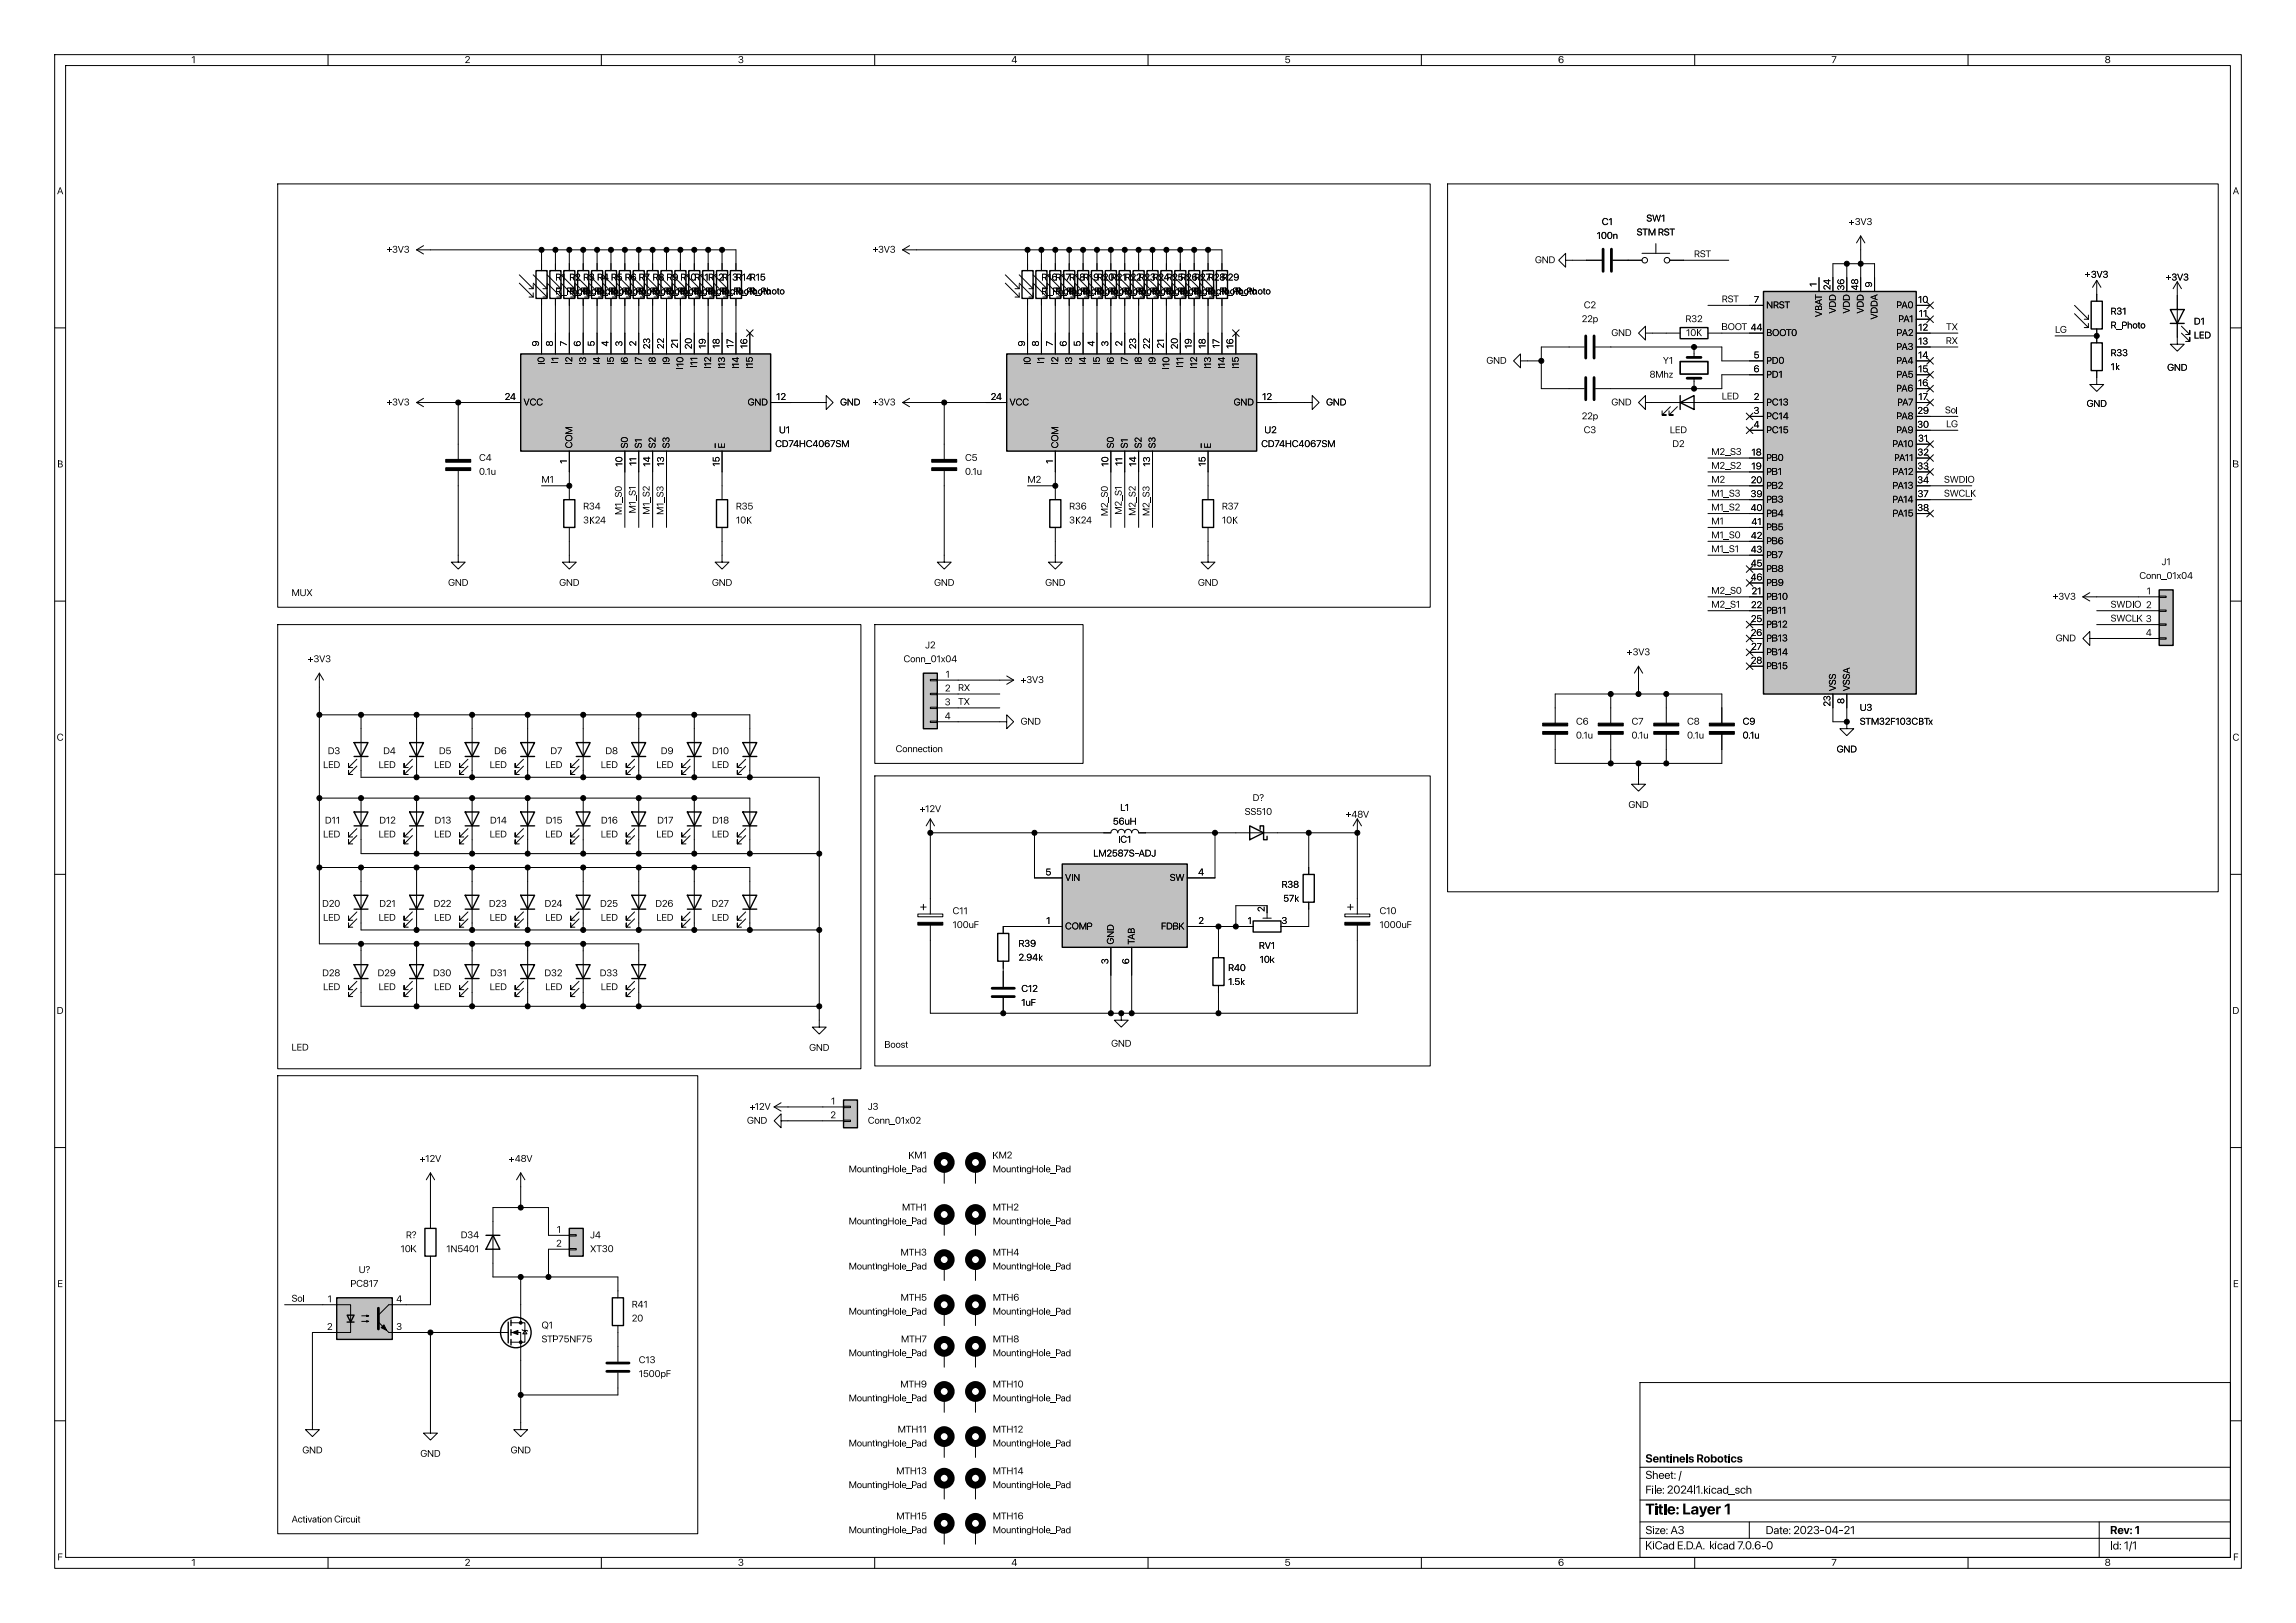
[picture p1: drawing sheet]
<svg xmlns="http://www.w3.org/2000/svg" width="420mm" height="297mm" viewBox="0 0 420 297" stroke-linecap="round" stroke-linejoin="round" font-family="sans-serif">
<defs><g id="words">
<text font-size="2.8" x="301" y="278">Title:Layer1</text>
<g font-size="2.1">
<text x="301" y="268.2">SentinelsRobotics</text>
<text x="301" y="273.9">File:2024l1.kicad_sch</text>
<text x="301" y="271.2">Sheet:/</text>
<text x="301" y="281.3">Size:A3</text>
<text x="323" y="281.3">Date:2023-04-21</text>
<text x="386" y="281.3">Rev:1</text>
<text x="301" y="284.1">KiCadE.D.A.kicad7.0.6-0</text>
<text x="386" y="284.1">Id:1/1</text>
</g>
<g font-size="1.8">
<text x="35" y="12.1">1</text>
<text x="85" y="12.1">2</text>
<text x="135" y="12.1">3</text>
<text x="185" y="12.1">4</text>
<text x="235" y="12.1">5</text>
<text x="285" y="12.1">6</text>
<text x="335" y="12.1">7</text>
<text x="385" y="12.1">8</text>
<text x="10.4" y="36.1">A</text>
<text x="293" y="41.7">C1</text>
<text x="301.2" y="41.1">SW1</text>
<text x="338.2" y="41.7">+3V3</text>
<text x="408.4" y="36.1">A</text>
<text x="70.7" y="46.8">+3V3</text>
<text x="159.6" y="46.8">+3V3</text>
<text x="292.1" y="44.2">100n</text>
<text x="299.4" y="43.6">STMRST</text>
<text x="309.9" y="47.3">RST</text>
<text x="101.6" y="51.9">R1R2R3R4R5R6R7R8R9R10R11R12R13R14R15</text>
<text x="190.5" y="51.9">R16R17R18R19R20R21R22R23R24R25R26R27R28R29</text>
<text x="280.8" y="48.7">GND</text>
<text x="332.5" y="52.5" transform="rotate(-90 332.5 52.5)">1</text>
<text x="335" y="53.1" transform="rotate(-90 335 53.1)">24</text>
<text x="337.6" y="53.1" transform="rotate(-90 337.6 53.1)">36</text>
<text x="340.1" y="53.1" transform="rotate(-90 340.1 53.1)">48</text>
<text x="342.6" y="52.6" transform="rotate(-90 342.6 52.6)">9</text>
<text x="381.4" y="51.3">+3V3</text>
<text x="396.1" y="51.9">+3V3</text>
<text x="101.6" y="54.4">R_Photo</text>
<text x="104.1" y="54.4">R_Photo</text>
<text x="106.7" y="54.4">R_Photo</text>
<text x="109.2" y="54.4">R_Photo</text>
<text x="116.8" y="54.4">R_Photo</text>
<text x="119.4" y="54.4">R_Photo</text>
<text x="127" y="54.4">R_Photo</text>
<text x="132.1" y="54.4">R_Photo</text>
<text x="134.6" y="54.4">R_Photo</text>
<text x="190.5" y="54.4">R_Photo</text>
<text x="193" y="54.4">R_Photo</text>
<text x="195.6" y="54.4">R_Photo</text>
<text x="200.7" y="54.4">R_Photo</text>
<text x="205.7" y="54.4">R_Photo</text>
<text x="210.8" y="54.4">R_Photo</text>
<text x="218.4" y="54.4">R_Photo</text>
<text x="223.5" y="54.4">R_Photo</text>
<text x="289.3" y="59.5">22p</text>
<text x="289.7" y="56.9">C2</text>
<text x="308.3" y="59.5">R32</text>
<text x="315" y="55.5">RST</text>
<text x="320.8" y="55.6">7</text>
<text x="323.1" y="56.9">NRST</text>
<text x="333.8" y="58" transform="rotate(-90 333.8 58)">VBAT</text>
<text x="336.3" y="57.4" transform="rotate(-90 336.3 57.4)">VDD</text>
<text x="338.9" y="57.4" transform="rotate(-90 338.9 57.4)">VDD</text>
<text x="341.4" y="57.4" transform="rotate(-90 341.4 57.4)">VDD</text>
<text x="344" y="58.5" transform="rotate(-90 344 58.5)">VDDA</text>
<text x="346.9" y="56.9">PA0</text>
<text x="347.2" y="59.5">PA1</text>
<text x="350.9" y="55.6">10</text>
<text x="351" y="58.2">11</text>
<text x="386.1" y="58.1">R31</text>
<text x="401.3" y="59.9">D1</text>
<text x="98.8" y="63.4" transform="rotate(-90 98.8 63.4)">9</text>
<text x="101.3" y="63.4" transform="rotate(-90 101.3 63.4)">8</text>
<text x="103.9" y="63.4" transform="rotate(-90 103.9 63.4)">7</text>
<text x="106.4" y="63.4" transform="rotate(-90 106.4 63.4)">6</text>
<text x="109" y="63.4" transform="rotate(-90 109 63.4)">5</text>
<text x="111.5" y="63.4" transform="rotate(-90 111.5 63.4)">4</text>
<text x="114" y="63.4" transform="rotate(-90 114 63.4)">3</text>
<text x="116.6" y="63.4" transform="rotate(-90 116.6 63.4)">2</text>
<text x="119.1" y="63.9" transform="rotate(-90 119.1 63.9)">23</text>
<text x="121.7" y="63.9" transform="rotate(-90 121.7 63.9)">22</text>
<text x="124.2" y="63.8" transform="rotate(-90 124.2 63.8)">21</text>
<text x="126.7" y="63.9" transform="rotate(-90 126.7 63.9)">20</text>
<text x="129.3" y="63.8" transform="rotate(-90 129.3 63.8)">19</text>
<text x="131.8" y="63.8" transform="rotate(-90 131.8 63.8)">18</text>
<text x="134.4" y="63.7" transform="rotate(-90 134.4 63.7)">17</text>
<text x="136.9" y="63.8" transform="rotate(-90 136.9 63.8)">16</text>
<text x="187.7" y="63.4" transform="rotate(-90 187.7 63.4)">9</text>
<text x="190.2" y="63.4" transform="rotate(-90 190.2 63.4)">8</text>
<text x="192.8" y="63.4" transform="rotate(-90 192.8 63.4)">7</text>
<text x="195.3" y="63.4" transform="rotate(-90 195.3 63.4)">6</text>
<text x="197.9" y="63.4" transform="rotate(-90 197.9 63.4)">5</text>
<text x="200.4" y="63.4" transform="rotate(-90 200.4 63.4)">4</text>
<text x="202.9" y="63.4" transform="rotate(-90 202.9 63.4)">3</text>
<text x="205.5" y="63.4" transform="rotate(-90 205.5 63.4)">2</text>
<text x="208" y="63.9" transform="rotate(-90 208 63.9)">23</text>
<text x="210.6" y="63.9" transform="rotate(-90 210.6 63.9)">22</text>
<text x="213.1" y="63.8" transform="rotate(-90 213.1 63.8)">21</text>
<text x="215.6" y="63.9" transform="rotate(-90 215.6 63.9)">20</text>
<text x="218.2" y="63.8" transform="rotate(-90 218.2 63.8)">19</text>
<text x="220.7" y="63.8" transform="rotate(-90 220.7 63.8)">18</text>
<text x="223.3" y="63.7" transform="rotate(-90 223.3 63.7)">17</text>
<text x="225.8" y="63.8" transform="rotate(-90 225.8 63.8)">16</text>
<text x="294.7" y="62">GND</text>
<text x="308.4" y="62">10K</text>
<text x="315" y="60.6">BOOT44</text>
<text x="320.2" y="60.7">44</text>
<text x="320.8" y="65.8">5</text>
<text x="323.1" y="62">BOOT0</text>
<text x="346.9" y="64.6">PA3</text>
<text x="346.9" y="62">PA2</text>
<text x="350.9" y="65.8">14</text>
<text x="350.9" y="63.2">13</text>
<text x="350.9" y="60.7">12</text>
<text x="355.9" y="63.2">RX</text>
<text x="356" y="60.6">TX</text>
<text x="375.9" y="61.1">LG</text>
<text x="386.1" y="60.6">R_Photo</text>
<text x="386.1" y="65.7">R33</text>
<text x="401.3" y="62.5">LED</text>
<text x="100.1" y="66.8" transform="rotate(-90 100.1 66.8)">I0</text>
<text x="102.7" y="66.5" transform="rotate(-90 102.7 66.5)">I1</text>
<text x="105.2" y="66.7" transform="rotate(-90 105.2 66.7)">I2</text>
<text x="107.7" y="66.7" transform="rotate(-90 107.7 66.7)">I3</text>
<text x="110.3" y="66.8" transform="rotate(-90 110.3 66.8)">I4</text>
<text x="112.8" y="66.7" transform="rotate(-90 112.8 66.7)">I5</text>
<text x="115.4" y="66.8" transform="rotate(-90 115.4 66.8)">I6</text>
<text x="117.9" y="66.6" transform="rotate(-90 117.9 66.6)">I7</text>
<text x="120.4" y="66.7" transform="rotate(-90 120.4 66.7)">I8</text>
<text x="123" y="66.8" transform="rotate(-90 123 66.8)">I9</text>
<text x="125.5" y="67.5" transform="rotate(-90 125.5 67.5)">I10</text>
<text x="128.1" y="67.3" transform="rotate(-90 128.1 67.3)">I11</text>
<text x="130.6" y="67.5" transform="rotate(-90 130.6 67.5)">I12</text>
<text x="133.1" y="67.5" transform="rotate(-90 133.1 67.5)">I13</text>
<text x="135.7" y="67.5" transform="rotate(-90 135.7 67.5)">I14</text>
<text x="138.2" y="67.5" transform="rotate(-90 138.2 67.5)">I15</text>
<text x="189" y="66.8" transform="rotate(-90 189 66.8)">I0</text>
<text x="191.6" y="66.5" transform="rotate(-90 191.6 66.5)">I1</text>
<text x="194.1" y="66.7" transform="rotate(-90 194.1 66.7)">I2</text>
<text x="196.6" y="66.7" transform="rotate(-90 196.6 66.7)">I3</text>
<text x="199.2" y="66.8" transform="rotate(-90 199.2 66.8)">I4</text>
<text x="201.7" y="66.7" transform="rotate(-90 201.7 66.7)">I5</text>
<text x="204.3" y="66.8" transform="rotate(-90 204.3 66.8)">I6</text>
<text x="206.8" y="66.6" transform="rotate(-90 206.8 66.6)">I7</text>
<text x="209.3" y="66.7" transform="rotate(-90 209.3 66.7)">I8</text>
<text x="211.9" y="66.8" transform="rotate(-90 211.9 66.8)">I9</text>
<text x="214.4" y="67.5" transform="rotate(-90 214.4 67.5)">I10</text>
<text x="217" y="67.3" transform="rotate(-90 217 67.3)">I11</text>
<text x="219.5" y="67.5" transform="rotate(-90 219.5 67.5)">I12</text>
<text x="222" y="67.5" transform="rotate(-90 222 67.5)">I13</text>
<text x="224.6" y="67.5" transform="rotate(-90 224.6 67.5)">I14</text>
<text x="227.1" y="67.5" transform="rotate(-90 227.1 67.5)">I15</text>
<text x="271.9" y="67.1">GND</text>
<text x="301.7" y="69.6">8Mhz</text>
<text x="304.2" y="67.1">Y1</text>
<text x="320.8" y="68.3">6</text>
<text x="323.1" y="67.1">PD0</text>
<text x="323.1" y="69.6">PD1</text>
<text x="346.9" y="67.1">PA4</text>
<text x="346.9" y="69.6">PA5</text>
<text x="350.8" y="70.9">16</text>
<text x="350.9" y="68.3">15</text>
<text x="386.1" y="68.2">1k</text>
<text x="396.4" y="68.4">GND</text>
<text x="70.7" y="74.7">+3V3</text>
<text x="92.3" y="73.4">24</text>
<text x="95.8" y="74.7">VCC</text>
<text x="136.8" y="74.7">GND</text>
<text x="142" y="73.4">12</text>
<text x="153.7" y="74.7">GND</text>
<text x="159.6" y="74.7">+3V3</text>
<text x="181.2" y="73.4">24</text>
<text x="184.7" y="74.7">VCC</text>
<text x="225.7" y="74.7">GND</text>
<text x="230.9" y="73.4">12</text>
<text x="242.6" y="74.7">GND</text>
<text x="289.3" y="77.3">22p</text>
<text x="294.7" y="74.7">GND</text>
<text x="315" y="73.3">LED</text>
<text x="320.8" y="75.9">3</text>
<text x="320.8" y="73.4">2</text>
<text x="323.1" y="74.7">PC13</text>
<text x="323.1" y="77.3">PC14</text>
<text x="346.9" y="72.2">PA6</text>
<text x="346.9" y="77.3">PA8</text>
<text x="347" y="74.7">PA7</text>
<text x="350.7" y="75.9">29</text>
<text x="350.9" y="73.4">17</text>
<text x="355.8" y="75.9">Sol</text>
<text x="381.7" y="75">GND</text>
<text x="105.2" y="82" transform="rotate(-90 105.2 82)">COM</text>
<text x="115.4" y="82" transform="rotate(-90 115.4 82)">S0</text>
<text x="117.9" y="82" transform="rotate(-90 117.9 82)">S1</text>
<text x="120.4" y="82" transform="rotate(-90 120.4 82)">S2</text>
<text x="123" y="82" transform="rotate(-90 123 82)">S3</text>
<text x="141.8" y="82.3">CD74HC4067SM</text>
<text x="142.5" y="79.8">U1</text>
<text x="194.1" y="82" transform="rotate(-90 194.1 82)">COM</text>
<text x="204.3" y="82" transform="rotate(-90 204.3 82)">S0</text>
<text x="206.8" y="82" transform="rotate(-90 206.8 82)">S1</text>
<text x="209.3" y="82" transform="rotate(-90 209.3 82)">S2</text>
<text x="211.9" y="82" transform="rotate(-90 211.9 82)">S3</text>
<text x="230.7" y="82.3">CD74HC4067SM</text>
<text x="231.3" y="79.8">U2</text>
<text x="289.7" y="79.8">C3</text>
<text x="305.5" y="79.8">LED</text>
<text x="305.9" y="82.3">D2</text>
<text x="313.1" y="83.5">M2_S3</text>
<text x="320.4" y="83.6">18</text>
<text x="320.8" y="78.5">4</text>
<text x="323.1" y="79.8">PC15</text>
<text x="346.2" y="82.3">PA10</text>
<text x="346.9" y="79.8">PA9</text>
<text x="350.7" y="78.5">30</text>
<text x="350.8" y="83.6">32</text>
<text x="350.9" y="81">31</text>
<text x="356" y="78.4">LG</text>
<text x="10.5" y="86.1">B</text>
<text x="87.6" y="84.9">C4</text>
<text x="87.6" y="87.4">0.1u</text>
<text x="99.1" y="88.6">M1</text>
<text x="103.9" y="84.8" transform="rotate(-90 103.9 84.8)">1</text>
<text x="114" y="85.4" transform="rotate(-90 114 85.4)">10</text>
<text x="116.6" y="85.2" transform="rotate(-90 116.6 85.2)">11</text>
<text x="119.1" y="85.4" transform="rotate(-90 119.1 85.4)">14</text>
<text x="121.7" y="85.4" transform="rotate(-90 121.7 85.4)">13</text>
<text x="131.8" y="85.4" transform="rotate(-90 131.8 85.4)">15</text>
<text x="176.5" y="84.9">C5</text>
<text x="176.5" y="87.4">0.1u</text>
<text x="188" y="88.6">M2</text>
<text x="192.8" y="84.8" transform="rotate(-90 192.8 84.8)">1</text>
<text x="202.9" y="85.4" transform="rotate(-90 202.9 85.4)">10</text>
<text x="205.5" y="85.2" transform="rotate(-90 205.5 85.2)">11</text>
<text x="208" y="85.4" transform="rotate(-90 208 85.4)">14</text>
<text x="210.6" y="85.4" transform="rotate(-90 210.6 85.4)">13</text>
<text x="220.7" y="85.4" transform="rotate(-90 220.7 85.4)">15</text>
<text x="313.1" y="86">M2_S2</text>
<text x="313.1" y="88.6">M2</text>
<text x="320.3" y="88.6">20</text>
<text x="320.4" y="86.1">19</text>
<text x="323.1" y="84.9">PB0</text>
<text x="323.1" y="87.4">PB1</text>
<text x="323.1" y="90">PB2</text>
<text x="346.2" y="90">PA13</text>
<text x="346.2" y="87.4">PA12</text>
<text x="346.4" y="84.9">PA11</text>
<text x="350.7" y="88.6">34</text>
<text x="350.7" y="86.1">33</text>
<text x="355.6" y="88.6">SWDIO</text>
<text x="408.4" y="86.1">B</text>
<text x="106.7" y="93.8">R34</text>
<text x="114" y="94.2" transform="rotate(-90 114 94.2)">M1_S0</text>
<text x="116.5" y="93.9" transform="rotate(-90 116.5 93.9)">M1_S1</text>
<text x="119" y="94.2" transform="rotate(-90 119 94.2)">M1_S2</text>
<text x="121.6" y="94.2" transform="rotate(-90 121.6 94.2)">M1_S3</text>
<text x="134.6" y="93.8">R35</text>
<text x="195.6" y="93.8">R36</text>
<text x="202.9" y="94.5" transform="rotate(-90 202.9 94.5)">M2_S0</text>
<text x="205.4" y="94.2" transform="rotate(-90 205.4 94.2)">M2_S1</text>
<text x="207.9" y="94.4" transform="rotate(-90 207.9 94.4)">M2_S2</text>
<text x="210.5" y="94.4" transform="rotate(-90 210.5 94.4)">M2_S3</text>
<text x="223.5" y="93.8">R37</text>
<text x="313.1" y="93.6">M1_S2</text>
<text x="313.1" y="91.1">M1_S3</text>
<text x="320.2" y="93.7">40</text>
<text x="320.2" y="91.2">39</text>
<text x="323.1" y="92.5">PB3</text>
<text x="323.1" y="95">PB4</text>
<text x="346.2" y="92.5">PA14</text>
<text x="346.2" y="95">PA15</text>
<text x="350.7" y="93.7">38</text>
<text x="350.8" y="91.2">37</text>
<text x="355.6" y="91.1">SWCLK</text>
<text x="106.7" y="96.3">3K24</text>
<text x="134.6" y="96.3">10K</text>
<text x="195.6" y="96.3">3K24</text>
<text x="223.5" y="96.3">10K</text>
<text x="313.1" y="98.7">M1_S0</text>
<text x="313.1" y="96.2">M1</text>
<text x="313.1" y="101.3">M1_S1</text>
<text x="320.2" y="101.3">43</text>
<text x="320.3" y="98.8">42</text>
<text x="320.4" y="96.3">41</text>
<text x="323.1" y="97.6">PB5</text>
<text x="323.1" y="100.1">PB6</text>
<text x="82" y="107.7">GND</text>
<text x="102.3" y="107.7">GND</text>
<text x="130.2" y="107.7">GND</text>
<text x="170.9" y="107.7">GND</text>
<text x="191.2" y="107.7">GND</text>
<text x="219.1" y="107.7">GND</text>
<text x="320.2" y="106.4">46</text>
<text x="320.3" y="103.9">45</text>
<text x="323.1" y="102.7">PB7</text>
<text x="323.1" y="105.2">PB8</text>
<text x="323.1" y="107.7">PB9</text>
<text x="391.3" y="106.5">Conn_01x04</text>
<text x="395.4" y="103.9">J1</text>
<text x="53.3" y="109.3">MUX</text>
<text x="313.1" y="111.4">M2_S1</text>
<text x="313.1" y="108.9">M2_S0</text>
<text x="320.3" y="111.5">22</text>
<text x="320.4" y="109">21</text>
<text x="323.1" y="110.3">PB10</text>
<text x="323.1" y="112.8">PB11</text>
<text x="375.5" y="110.3">+3V3</text>
<text x="386.1" y="111.4">SWDIO 2</text>
<text x="386.1" y="114">SWCLK3</text>
<text x="392.7" y="109">1</text>
<text x="169.2" y="119.2">J2</text>
<text x="320.3" y="116.6">26</text>
<text x="320.3" y="114">25</text>
<text x="320.3" y="119.1">27</text>
<text x="323.1" y="115.4">PB12</text>
<text x="323.1" y="117.9">PB13</text>
<text x="376" y="117.9">GND</text>
<text x="392.5" y="116.6">4</text>
<text x="56.3" y="121.7">+3V3</text>
<text x="165.3" y="121.7">Conn_01x04</text>
<text x="173" y="124.2">1</text>
<text x="186.7" y="125.5">+3V3</text>
<text x="297.6" y="120.4">+3V3</text>
<text x="320.3" y="121.7">28</text>
<text x="323.1" y="120.4">PB14</text>
<text x="323.1" y="123">PB15</text>
<text x="172.8" y="131.8">4</text>
<text x="172.8" y="129.3">3</text>
<text x="172.9" y="126.7">2</text>
<text x="175.3" y="129.2">TX</text>
<text x="175.3" y="126.7">RX</text>
<text x="335" y="129.3" transform="rotate(-90 335 129.3)">23</text>
<text x="336.3" y="126.5" transform="rotate(-90 336.3 126.5)">VSS</text>
<text x="337.6" y="128.8" transform="rotate(-90 337.6 128.8)">8</text>
<text x="338.9" y="126.5" transform="rotate(-90 338.9 126.5)">VSSA</text>
<text x="340.2" y="130.6">U3</text>
<text x="10.4" y="136.1">C</text>
<text x="163.8" y="137.8">Connection</text>
<text x="186.7" y="133.1">GND</text>
<text x="288.3" y="133.1">C6</text>
<text x="288.3" y="135.7">0.1u</text>
<text x="298.4" y="133.1">C7</text>
<text x="298.4" y="135.7">0.1u</text>
<text x="308.6" y="133.1">C8</text>
<text x="308.6" y="135.7">0.1u</text>
<text x="318.8" y="133.1">C9</text>
<text x="318.8" y="135.7">0.1u</text>
<text x="340.2" y="133.1">STM32F103CBTx</text>
<text x="408.4" y="136.1">C</text>
<text x="59.1" y="141.1">LED</text>
<text x="60" y="138.5">D3</text>
<text x="69.3" y="141.1">LED</text>
<text x="70.1" y="138.5">D4</text>
<text x="79.4" y="141.1">LED</text>
<text x="80.3" y="138.5">D5</text>
<text x="89.6" y="141.1">LED</text>
<text x="90.4" y="138.5">D6</text>
<text x="99.8" y="141.1">LED</text>
<text x="100.7" y="138.5">D7</text>
<text x="109.9" y="141.1">LED</text>
<text x="110.8" y="138.5">D8</text>
<text x="120.1" y="141.1">LED</text>
<text x="120.9" y="138.5">D9</text>
<text x="130.2" y="141.1">LED</text>
<text x="130.3" y="138.5">D10</text>
<text x="336" y="138.2">GND</text>
<text x="168.2" y="149.1">+12V</text>
<text x="204.9" y="148.9">L1</text>
<text x="227.7" y="149.6">SS510</text>
<text x="229.1" y="147.1">D?</text>
<text x="297.9" y="148.4">GND</text>
<text x="59.1" y="153.8">LED</text>
<text x="59.4" y="151.2">D11</text>
<text x="69.3" y="153.8">LED</text>
<text x="69.4" y="151.2">D12</text>
<text x="79.4" y="153.8">LED</text>
<text x="79.5" y="151.2">D13</text>
<text x="89.6" y="153.8">LED</text>
<text x="89.6" y="151.2">D14</text>
<text x="99.8" y="153.8">LED</text>
<text x="99.8" y="151.2">D15</text>
<text x="109.9" y="153.8">LED</text>
<text x="109.9" y="151.2">D16</text>
<text x="120.1" y="153.8">LED</text>
<text x="120.2" y="151.2">D17</text>
<text x="130.2" y="153.8">LED</text>
<text x="130.3" y="151.2">D18</text>
<text x="203.6" y="151.4">56uH</text>
<text x="204.5" y="154.7">IC1</text>
<text x="246.1" y="150.2">+48V</text>
<text x="191.3" y="160.4">5</text>
<text x="194.8" y="161.7">VIN</text>
<text x="200" y="157.3">LM2587S-ADJ</text>
<text x="214" y="161.7">SW</text>
<text x="219.2" y="160.4">4</text>
<text x="58.9" y="166.5">D20</text>
<text x="69.4" y="166.5">D21</text>
<text x="79.3" y="166.5">D22</text>
<text x="89.4" y="166.5">D23</text>
<text x="99.6" y="166.5">D24</text>
<text x="109.8" y="166.5">D25</text>
<text x="119.9" y="166.5">D26</text>
<text x="130.2" y="166.5">D27</text>
<text x="174.2" y="167.8">C11</text>
<text x="231.5" y="166.9" transform="rotate(-90 231.5 166.9)">2</text>
<text x="234.4" y="163">R38</text>
<text x="234.7" y="165.5">57k</text>
<text x="252.3" y="167.8">C10</text>
<text x="59.1" y="169">LED</text>
<text x="69.3" y="169">LED</text>
<text x="79.4" y="169">LED</text>
<text x="89.6" y="169">LED</text>
<text x="99.8" y="169">LED</text>
<text x="109.9" y="169">LED</text>
<text x="120.1" y="169">LED</text>
<text x="130.2" y="169">LED</text>
<text x="174.2" y="170.3">100uF</text>
<text x="186.3" y="173.8">R39</text>
<text x="191.4" y="169.3">1</text>
<text x="194.8" y="170.6">COMP</text>
<text x="204.3" y="172.8" transform="rotate(-90 204.3 172.8)">GND</text>
<text x="208.1" y="172.8" transform="rotate(-90 208.1 172.8)">TAB</text>
<text x="212.4" y="170.6">FDBK</text>
<text x="219.2" y="169.3">2</text>
<text x="228.2" y="169.3">1</text>
<text x="234.4" y="169.3">3</text>
<text x="252.3" y="170.3">1000uF</text>
<text x="59" y="179.2">D28</text>
<text x="69.1" y="179.2">D29</text>
<text x="79.2" y="179.2">D30</text>
<text x="89.7" y="179.2">D31</text>
<text x="99.6" y="179.2">D32</text>
<text x="109.7" y="179.2">D33</text>
<text x="186.3" y="176.3">2.94k</text>
<text x="202.9" y="176.4" transform="rotate(-90 202.9 176.4)">3</text>
<text x="206.8" y="176.4" transform="rotate(-90 206.8 176.4)">6</text>
<text x="224.7" y="178.2">R40</text>
<text x="230.3" y="174.2">RV1</text>
<text x="230.4" y="176.7">10k</text>
<text x="59.1" y="181.7">LED</text>
<text x="69.3" y="181.7">LED</text>
<text x="79.4" y="181.7">LED</text>
<text x="89.6" y="181.7">LED</text>
<text x="99.8" y="181.7">LED</text>
<text x="109.9" y="181.7">LED</text>
<text x="186.8" y="182">C12</text>
<text x="186.8" y="184.6">1uF</text>
<text x="224.7" y="180.8">1.5k</text>
<text x="10.4" y="186.1">D</text>
<text x="161.8" y="191.9">Boost</text>
<text x="408.4" y="186.1">D</text>
<text x="53.3" y="192.5">LED</text>
<text x="148" y="192.8">GND</text>
<text x="203.3" y="192.1">GND</text>
<text x="137" y="203.6">+12V</text>
<text x="152" y="202.3">1</text>
<text x="158.7" y="203.6">J3</text>
<text x="136.6" y="206.2">GND</text>
<text x="151.9" y="204.9">2</text>
<text x="158.7" y="206.2">Conn_01x02</text>
<text x="76.8" y="213.1">+12V</text>
<text x="93.1" y="213.1">+48V</text>
<text x="155.3" y="215">MountingHole_Pad</text>
<text x="166.2" y="212.5">KM1</text>
<text x="181.6" y="212.5">KM2</text>
<text x="181.6" y="215">MountingHole_Pad</text>
<text x="74.3" y="227.1">R?</text>
<text x="84.3" y="227.1">D34</text>
<text x="101.8" y="225.8">1</text>
<text x="107.9" y="227.1">J4</text>
<text x="155.3" y="224.6">MountingHole_Pad</text>
<text x="165" y="222">MTH1</text>
<text x="181.6" y="222">MTH2</text>
<text x="181.6" y="224.6">MountingHole_Pad</text>
<text x="65.6" y="233.5">U?</text>
<text x="73.3" y="229.7">10K</text>
<text x="81.6" y="229.7">1N5401</text>
<text x="101.7" y="228.3">2</text>
<text x="107.9" y="229.7">XT30</text>
<text x="155.3" y="232.8">MountingHole_Pad</text>
<text x="164.7" y="230.3">MTH3</text>
<text x="181.6" y="230.3">MTH4</text>
<text x="181.6" y="232.8">MountingHole_Pad</text>
<text x="10.5" y="236.1">E</text>
<text x="53.3" y="238.4">Sol</text>
<text x="59.9" y="238.5">1</text>
<text x="64.1" y="236">PC817</text>
<text x="72.5" y="238.5">4</text>
<text x="115.6" y="239.8">R41</text>
<text x="164.8" y="238.5">MTH5</text>
<text x="181.6" y="238.5">MTH6</text>
<text x="408.5" y="236.1">E</text>
<text x="59.8" y="243.6">2</text>
<text x="72.5" y="243.6">3</text>
<text x="99.1" y="243.6">Q1</text>
<text x="115.6" y="242.4">20</text>
<text x="155.3" y="241.1">MountingHole_Pad</text>
<text x="181.6" y="241.1">MountingHole_Pad</text>
<text x="99.1" y="246.2">STP75NF75</text>
<text x="116.8" y="250">C13</text>
<text x="155.3" y="248.7">MountingHole_Pad</text>
<text x="164.8" y="246.2">MTH7</text>
<text x="181.6" y="246.2">MTH8</text>
<text x="181.6" y="248.7">MountingHole_Pad</text>
<text x="116.8" y="252.5">1500pF</text>
<text x="155.3" y="257">MountingHole_Pad</text>
<text x="164.7" y="254.4">MTH9</text>
<text x="181.6" y="254.4">MTH10</text>
<text x="181.6" y="257">MountingHole_Pad</text>
<text x="164.2" y="262.7">MTH11</text>
<text x="181.6" y="262.7">MTH12</text>
<text x="55.3" y="266.5">GND</text>
<text x="76.9" y="267.1">GND</text>
<text x="93.4" y="266.5">GND</text>
<text x="155.3" y="265.2">MountingHole_Pad</text>
<text x="181.6" y="265.2">MountingHole_Pad</text>
<text x="155.3" y="272.8">MountingHole_Pad</text>
<text x="164" y="270.3">MTH13</text>
<text x="181.6" y="270.3">MTH14</text>
<text x="181.6" y="272.8">MountingHole_Pad</text>
<text x="53.3" y="278.8">ActivationCircuit</text>
<text x="155.3" y="281.1">MountingHole_Pad</text>
<text x="164" y="278.5">MTH15</text>
<text x="181.6" y="278.5">MTH16</text>
<text x="181.6" y="281.1">MountingHole_Pad</text>
<text x="10.5" y="286.1">F</text>
<text x="35" y="287.1">1</text>
<text x="85" y="287.1">2</text>
<text x="135" y="287.1">3</text>
<text x="185" y="287.1">4</text>
<text x="235" y="287.1">5</text>
<text x="285" y="287.1">6</text>
<text x="335" y="287.1">7</text>
<text x="385" y="287.1">8</text>
<text x="408.5" y="286.1">F</text>
</g>
</g></defs>
<g fill="none" stroke="#000" stroke-width=".18">
<path d="M10 10h400v277h-400zM12 12h396v273h-396zM60 10v2M110 10v2M160 10v2M210 10v2M260 10v2M310 10v2M360 10v2M50.8 33.7h210.8v77.4h-210.8zM264.8 33.7h141v129.5h-141zM10 60h2"/>
<path d="M76.2 45.7h58.4v3.8M76.2 45.7l1.3 .8M77.5 45l-1.3 .7M95 51.8l2.5 2.6M95 50.3l2.5 2.5M96.8 54.4h.7M96.8 52.8h.7M97.5 51.8l2.6 2.6M97.5 50.3l2.6 2.5M97.5 52.1v.7M97.5 53.6v.8M99.1 45.7v3.8"/>
<path d="M99.1 54.6v10.2M99.3 54.4h.8M99.3 52.8h.8M100.1 52.1v.7M100.1 53.6v.8M100.1 51.8l2.5 2.6M100.1 50.3l2.5 2.5v-.7M101.6 45.7v3.8M101.6 54.6v10.2M102.6 51.8l2.6 2.6M102.6 50.3l2.6 2.5v-.7M104.1 45.7v3.8"/>
<path d="M104.1 54.6v10.2M105.2 51.8l2.5 2.6M105.2 50.3l2.5 2.5v-.7M106.7 45.7v3.8M106.7 54.6v10.2M107.7 51.8l2.5 2.6M107.7 50.3l2.5 2.5v-.7M109.2 45.7v3.8M109.2 54.6v10.2M110.2 51.8l2.6 2.6M110.2 50.3l2.6 2.5v-.7M111.8 45.7v3.8"/>
<path d="M111.8 54.6v10.2M112.8 51.8l2.5 2.6M112.8 50.3l2.5 2.5v-.7M114.3 45.7v3.8M114.3 54.6v10.2M115.3 51.8l2.6 2.6M115.3 50.3l2.6 2.5v-.7M116.8 45.7v3.8M116.8 54.6v10.2M117.9 51.8l2.5 2.6M117.9 50.3l2.5 2.5v-.7M119.4 45.7v3.8"/>
<path d="M119.4 54.6v10.2M120.4 51.8l2.5 2.6M120.4 50.3l2.5 2.5v-.7M121.9 45.7v3.8M121.9 54.6v10.2M122.9 51.8l2.6 2.6M122.9 50.3l2.6 2.5v-.7M124.5 45.7v3.8M124.5 54.6v10.2M125.5 51.8l2.5 2.6M125.5 50.3l2.5 2.5v-.7M127 45.7v3.8"/>
<path d="M127 54.6v10.2M128 51.8l2.6 2.6M128 50.3l2.6 2.5v-.7M129.5 45.7v3.8M129.5 54.6v10.2M130.6 51.8l2.5 2.6M130.6 50.3l2.5 2.5v-.7M132.1 45.7v3.8M132.1 54.6v10.2M134.6 54.6v10.2M165.1 45.7h58.4v3.8M165.1 45.7l1.3 .8"/>
<path d="M166.4 45l-1.3 .7M183.9 51.8l2.5 2.6M183.9 50.3l2.5 2.5M185.7 54.4h.7M185.7 52.8h.7M186.4 52.1v.7M186.4 53.6v.8M186.4 51.8l2.6 2.6M186.4 50.3l2.6 2.5M188 45.7v3.8M188 54.6v10.2M188.2 54.4h.8"/>
<path d="M188.2 52.8h.8M189 51.8l2.5 2.6M189 50.3l2.5 2.5v-.7M189 52.1v.7M189 53.6v.8M190.5 45.7v3.8M190.5 54.6v10.2M191.5 51.8l2.6 2.6M191.5 50.3l2.6 2.5v-.7M193 45.7v3.8M193 54.6v10.2M194.1 51.8l2.5 2.6"/>
<path d="M194.1 50.3l2.5 2.5v-.7M195.6 45.7v3.8M195.6 54.6v10.2M196.6 51.8l2.5 2.6M196.6 50.3l2.5 2.5v-.7M198.1 45.7v3.8M198.1 54.6v10.2M199.1 51.8l2.6 2.6M199.1 50.3l2.6 2.5v-.7M200.7 45.7v3.8M200.7 54.6v10.2M201.7 51.8l2.5 2.6"/>
<path d="M201.7 50.3l2.5 2.5v-.7M203.2 45.7v3.8M203.2 54.6v10.2M204.2 51.8l2.6 2.6M204.2 50.3l2.6 2.5v-.7M205.7 45.7v3.8M205.7 54.6v10.2M206.8 51.8l2.5 2.6M206.8 50.3l2.5 2.5v-.7M208.3 45.7v3.8M208.3 54.6v10.2M209.3 51.8l2.5 2.6"/>
<path d="M209.3 50.3l2.5 2.5v-.7M210.8 45.7v3.8M210.8 54.6v10.2M211.8 51.8l2.6 2.6M211.8 50.3l2.6 2.5v-.7M213.4 45.7v3.8M213.4 54.6v10.2M214.4 51.8l2.5 2.6M214.4 50.3l2.5 2.5v-.7M215.9 45.7v3.8M215.9 54.6v10.2M216.9 51.8l2.6 2.6"/>
<path d="M216.9 50.3l2.6 2.5v-.7M218.4 45.7v3.8M218.4 54.6v10.2M219.5 51.8l2.5 2.6M219.5 50.3l2.5 2.5v-.7M221 45.7v3.8M221 54.6v10.2M223.5 54.6v10.2M286.4 47.6v-1.2l-1.3 1.2 1.3 1.3v-1.3h6.6M295 47.6h5.4M300.4 46.4h5M302.9 44.6v1.8"/>
<path d="M305.4 47.6h10.8M312.4 55.9h10.2M332.7 50.8v2.5M335.3 50.8v-2.5h7.6v5M337.8 48.3v2.5M340.4 43.2l-.8 1.3M340.4 43.2v7.6M340.4 43.2l.7 1.3M350.5 58.4h2.6M352.5 57.8l1.2 1.2M352.5 55.3l1.2 1.2M353.7 57.8l-1.2 1.2"/>
<path d="M353.7 55.3l-1.2 1.2M379.5 57.4l2.5 2.5M379.5 55.9l2.5 2.5M381.3 59.9h.7M381.3 58.4h.7M382 57.7v.7M382 59.2v.7M383.5 51.3l-.7 1.3M383.5 51.3v3.8M383.5 51.3l.8 1.3M398.3 51.6v11.4h1.2l-1.2 1.3-1.3-1.3h1.3M398.3 51.6l-.8 1.2"/>
<path d="M398.3 51.6l.7 1.2M399 59.7l1.6 1.5v-.7v.7h-.8M408 60h2M76.2 73.7h19M76.2 73.7l1.3 .7M77.5 72.9l-1.3 .8M83.8 73.7v10.4M136.6 60.4l1.2 1.2M137.2 61v3.8M137.8 60.4l-1.2 1.2M141 73.7h10.1v-1.3l1.3 1.3-1.3 1.2v-1.2M165.1 73.7h19"/>
<path d="M165.1 73.7l1.3 .7M166.4 72.9l-1.3 .8M172.7 73.7v10.4M225.5 60.4l1.2 1.2M226.1 61v3.8M226.7 60.4l-1.2 1.2M229.9 73.7h10.1v-1.3l1.3 1.3-1.3 1.2v-1.2M278.1 66v-1.2l-1.2 1.2 1.2 1.3v-1.3h3.8M289.8 63.5h-7.9v7.6h7.9M291.8 63.5h23.2v2.5h7.6M301 73.7v-1.3l-1.3 1.3 1.3 1.2v-1.2h21.6M301 61v-1.3l-1.3 1.3 1.3 1.2v-1.2h6.3"/>
<path d="M305.6 74.4l-1.6 1.5h.8h-.8v-.7M306.8 74.4l-1.5 1.5h.8h-.8v-.7M309.9 63.5v1.9M309.9 69.2v1.9M312.4 61h7.6M319.4 78.1l1.2 1.2M319.4 75.6l1.2 1.2M320 76.2h2.6M320 78.7h2.6M320.6 78.1l-1.2 1.2M320.6 75.6l-1.2 1.2M322.6 68.6h-7.6v2.5h-23.2"/>
<path d="M352.5 70.5l1.2 1.2M352.5 73.1l1.2 1.2M352.5 68l1.2 1.2M352.5 65.4l1.2 1.2M353.1 61h5M353.1 76.2h5M353.1 78.7h5M353.1 63.5h5M353.7 70.5l-1.2 1.2M353.7 73.1l-1.2 1.2M353.7 68l-1.2 1.2M353.7 65.4l-1.2 1.2"/>
<path d="M375.9 61.5h7.6M383.5 67.8v2.6h1.3l-1.3 1.2-1.2-1.2h1.2M383.5 60.2v2.5M399 61l1.6 1.5v-.8v.8h-.8M83.8 86.1v16.8h1.3l-1.3 1.2-1.3-1.2h1.3M99.1 88.9h5M104.1 96.5v6.4h1.3l-1.3 1.2-1.2-1.2h1.2M104.1 82.6v8.8M114.3 82.6v13.9M116.8 82.6v13.9M119.4 82.6v13.9M121.9 82.6v13.9"/>
<path d="M130.8 81.2v.7M132.1 96.5v6.4h1.2l-1.2 1.2-1.3-1.2h1.3M132.1 82.6v8.8M172.7 86.1v16.8h1.3l-1.3 1.2-1.3-1.2h1.3M188 88.9h5M193 96.5v6.4h1.3l-1.3 1.2-1.2-1.2h1.2M193 82.6v8.8M203.2 82.6v13.9M205.7 82.6v13.9M208.3 82.6v13.9M210.8 82.6v13.9M219.7 81.2v.7"/>
<path d="M221 96.5v6.4h1.2l-1.2 1.2-1.3-1.2h1.3M221 82.6v8.8M312.4 88.9h7.6M312.4 91.4h7.6M312.4 99.1h7.6M312.4 96.5h7.6M312.4 86.4h7.6M312.4 94h7.6M312.4 83.8h7.6M352.5 80.7l1.2 1.2M352.5 93.4l1.2 1.2M352.5 83.2l1.2 1.2"/>
<path d="M352.5 85.8l1.2 1.2M353.1 88.9h7.6M353.1 91.4h7.6M353.7 80.7l-1.2 1.2M353.7 85.8l-1.2 1.2M353.7 83.2l-1.2 1.2M353.7 93.4l-1.2 1.2M10 110h2M50.8 114.3h106.7v81.3h-106.7zM160 114.3h38.1v25.4h-38.1zM312.4 109.2h7.6M312.4 111.8h7.6"/>
<path d="M312.4 101.6h7.6M319.4 118.8l1.2 1.2M319.4 116.2l1.2 1.2M319.4 113.7l1.2 1.2M319.4 106.1l1.2 1.2M319.4 103.5l1.2 1.2M320.6 103.5l-1.2 1.2M320.6 106.1l-1.2 1.2M320.6 113.7l-1.2 1.2M320.6 118.8l-1.2 1.2M320.6 116.2l-1.2 1.2M381 109.2h14"/>
<path d="M381 109.2l1.3 .8M382.3 116.8v-1.2l-1.3 1.2 1.3 1.3v-1.3h12.7M382.3 108.5l-1.3 .7M383.5 111.8h11.5M383.5 114.3h11.5M395 116.7h1.2v.3h-1.2zM395 114.2h1.2v.2h-1.2zM395 111.6h1.2v.3h-1.2zM395 109.1h1.2v.2h-1.2zM408 110h2M58.4 123.2v49.5h58.4v11.5M58.4 130.8h78.8v11.4"/>
<path d="M58.4 123.2l-.7 1.3M58.4 123.2l.8 1.3M65.3 138.9l-1.5 1.6v-.8v.8h.7M66 130.8v11.4h83.9v45.8h1.2l-1.2 1.2-1.3-1.2h1.3M75.4 138.9l-1.5 1.6v-.8v.8h.8M76.2 130.8v11.4M85.6 138.9l-1.5 1.6v-.8v.8h.7M86.4 130.8v11.4M95.8 138.9l-1.6 1.6v-.8v.8h.8M96.5 130.8v11.4M105.9 138.9l-1.5 1.6v-.8v.8h.8M106.7 130.8v11.4"/>
<path d="M116.1 138.9l-1.5 1.6v-.8v.8h.7M116.8 130.8v11.4M126.2 138.9l-1.5 1.6v-.8v.8h.8M127 130.8v11.4M136.4 138.9l-1.5 1.6v-.8v.8h.7M170.2 132h1.2v.2h-1.2zM170.2 129.4h1.2v.3h-1.2zM170.2 126.9h1.2v.2h-1.2zM170.2 124.3h1.2v.3h-1.2zM171.4 132.1h12.7v-1.3l1.3 1.3-1.3 1.3v-1.3M171.4 124.5h14M171.4 127h11.5"/>
<path d="M171.4 129.5h11.5M184.1 123.7l1.3 .8M185.4 124.5l-1.3 .7M284.5 132.3v-5.3h30.5v5.3M284.5 134.4v5.3h30.5v-5.3M294.6 127v5.3M294.6 134.4v5.3M299.7 139.7v3.8h1.3l-1.3 1.3-1.3-1.3h1.3M299.7 121.9l-.7 1.3M299.7 121.9v5.1M299.7 121.9l.8 1.3M304.8 127v5.3"/>
<path d="M304.8 134.4v5.3M319.4 121.3l1.2 1.2M320.6 121.3l-1.2 1.2M335.3 129.5v2.6h2.5M337.8 132.1v1.3h1.3l-1.3 1.2-1.3-1.2h1.3M337.8 127v5.1M10 160h2M58.4 146.1h78.8v10.1M58.4 158.8h78.8v11.4M65.3 152.9l-1.5 1.5v-.7v.7h.7M65.3 151.6l-1.5 1.6v-.8v.8h.7M65.3 140.2l-1.5 1.5v-.7v.7h.7"/>
<path d="M66 146.1v10.1h83.9M66 158.8v11.4h83.9M75.4 152.9l-1.5 1.5v-.7v.7h.8M75.4 151.6l-1.5 1.6v-.8v.8h.8M75.4 140.2l-1.5 1.5v-.7v.7h.8M76.2 146.1v10.1M76.2 158.8v11.4M85.6 152.9l-1.5 1.5v-.7v.7h.7M85.6 151.6l-1.5 1.6v-.8v.8h.7M85.6 140.2l-1.5 1.5v-.7v.7h.7M86.4 146.1v10.1M86.4 158.8v11.4"/>
<path d="M95.8 152.9l-1.6 1.5v-.7v.7h.8M95.8 151.6l-1.6 1.6v-.8v.8h.8M95.8 140.2l-1.6 1.5v-.7v.7h.8M96.5 146.1v10.1M96.5 158.8v11.4M105.9 140.2l-1.5 1.5v-.7v.7h.8M105.9 152.9l-1.5 1.5v-.7v.7h.8M105.9 151.6l-1.5 1.6v-.8v.8h.8M106.7 146.1v10.1M106.7 158.8v11.4M116.1 140.2l-1.5 1.5v-.7v.7h.7M116.1 152.9l-1.5 1.5v-.7v.7h.7"/>
<path d="M116.1 151.6l-1.5 1.6v-.8v.8h.7M116.8 146.1v10.1M116.8 158.8v11.4M126.2 140.2l-1.5 1.5v-.7v.7h.8M126.2 152.9l-1.5 1.5v-.7v.7h.8M126.2 151.6l-1.5 1.6v-.8v.8h.8M127 146.1v10.1M127 158.8v11.4M136.4 140.2l-1.5 1.5v-.7v.7h.7M136.4 152.9l-1.5 1.5v-.7v.7h.7M136.4 151.6l-1.5 1.6v-.8v.8h.7M160 142h101.6v53.1h-101.6z"/>
<path d="M170.2 152.4h33a.64 .64 0 0 1 .6-.6 .64 .64 0 0 1 .7 .6 .64 .64 0 0 1 .6-.6 .64 .64 0 0 1 .6 .6 .64 .64 0 0 1 .7-.6 .64 .64 0 0 1 .6 .6 .64 .64 0 0 1 .6-.6 .64 .64 0 0 1 .7 .6h40M170.2 149.9l-.8 1.2M170.2 149.9v17.4M170.2 149.9l.7 1.2M189.2 152.4v8.3h5.1M222.2 152.4v8.3h-5M239.4 152.4v7.6M248.3 149.9v17.4M248.3 149.9l-.8 1.2M248.3 149.9l.7 1.2M408 160h2M65.3 179.6l-1.5 1.5v-.8v.8h.7"/>
<path d="M65.3 168.1l-1.5 1.6v-.8v.8h.7M65.3 166.9l-1.5 1.5v-.8v.8h.7M66 172.7v11.5h83.9M75.4 179.6l-1.5 1.5v-.8v.8h.8M75.4 168.1l-1.5 1.6v-.8v.8h.8M75.4 166.9l-1.5 1.5v-.8v.8h.8M76.2 172.7v11.5M85.6 179.6l-1.5 1.5v-.8v.8h.7M85.6 168.1l-1.5 1.6v-.8v.8h.7M85.6 166.9l-1.5 1.5v-.8v.8h.7M86.4 172.7v11.5M95.8 168.1l-1.6 1.6v-.8v.8h.8"/>
<path d="M95.8 166.9l-1.6 1.5v-.8v.8h.8M95.8 179.6l-1.6 1.5v-.8v.8h.8M96.5 172.7v11.5M105.9 168.1l-1.5 1.6v-.8v.8h.8M105.9 166.9l-1.5 1.5v-.8v.8h.8M105.9 179.6l-1.5 1.5v-.8v.8h.8M106.7 172.7v11.5M116.1 168.1l-1.5 1.6v-.8v.8h.7M116.1 166.9l-1.5 1.5v-.8v.8h.7M116.1 179.6l-1.5 1.5v-.8v.8h.7M126.2 168.1l-1.5 1.6v-.8v.8h.8M126.2 166.9l-1.5 1.5v-.8v.8h.8"/>
<path d="M136.4 168.1l-1.5 1.6v-.8v.8h.7M136.4 166.9l-1.5 1.5v-.8v.8h.7M167.9 167.3h4.6v.5h-4.6zM168.4 166h1M168.9 165.5v1M170.2 169.3v16.1h78.1v-16.1M183.5 175.9v4.7M194.3 169.5h-10.8v1.3M203.2 173.4v12M207 173.4v12M217.2 169.5h10.8M222.9 169.5v5.8"/>
<path d="M231 168h1.5M231.8 165.7h-5.7v3.8M231.8 167v1M239.4 165.1v4.4h-3.8M246 167.3h4.6v.5h-4.6zM246.5 166h1M247 165.5v1M50.8 196.9h76.8v83.8h-76.8zM65.3 180.8l-1.5 1.6v-.8v.8h.7M75.4 180.8l-1.5 1.6v-.8v.8h.8M85.6 180.8l-1.5 1.6v-.8v.8h.7M95.8 180.8l-1.6 1.6v-.8v.8h.8"/>
<path d="M105.9 180.8l-1.5 1.6v-.8v.8h.8M116.1 180.8l-1.5 1.6v-.8v.8h.7M183.5 182.6v2.8M205.1 185.4v1.3h1.3l-1.3 1.3-1.3-1.3h1.3M222.9 180.3v5.1M10 210h2M78.7 214.6v10.2M78.7 214.6l-.7 1.3M78.7 214.6l.8 1.3M95.2 214.6v6.4M95.2 214.6l-.7 1.3M95.2 214.6l.8 1.3"/>
<path d="M141.6 202.6h12.7M141.6 202.6l1.3 .7M142.9 205.1v-1.3l-1.3 1.3 1.3 1.3v-1.3h11.4M142.9 201.8l-1.3 .8M154.3 205h1.3v.2h-1.3zM154.3 202.4h1.3v.3h-1.3zM172.7 214v2.5M178.4 214v2.5M408 210h2M52.1 238.8h12v5h-7v17.8h1.3l-1.3 1.3-1.2-1.3h1.2M78.7 229.9v8.9h-7.6l-1.9 1.9M95.2 233.7v8.4"/>
<path d="M104.1 228.5h1.3v.2h-1.3zM104.1 225.9h1.3v.3h-1.3zM104.1 226.1h-3.8v-5.1h-10.1v12.7h22.8v3.8M104.1 228.6h-3.8v5.1M172.7 223.5v2.6M172.7 231.8v2.5M178.4 223.5v2.6M178.4 231.8v2.5M10 260h2M66.2 241.8h1.2l-.3 .1v-.2l.3 .1M66.2 240.8h1.2l-.3 .1v-.2l.3 .1M71.1 243.8h21.9"/>
<path d="M78.7 243.8v18.5h1.3l-1.3 1.2-1.2-1.2h1.2M93.5 243.8h1.7v17.8h1.3l-1.3 1.3-1.2-1.3h1.2M93.5 242.1h2.5v3.5h-2.5M95.5 243.3l.1 .2h.8l.1 .1M96 243.5l.4 .6h-.8zM113 242.6v6.6M113 251.2v4.1h-17.8M172.7 240v2.6M172.7 247.6v2.6M172.7 255.9v2.5M178.4 240v2.6M178.4 247.6v2.6"/>
<path d="M178.4 255.9v2.5M300 253h108v32h-108zM408 260h2M172.7 264.2v2.5M172.7 271.8v2.5M178.4 264.2v2.5M178.4 271.8v2.5M300 278.5h108M300 274.5h108M300 268.5h108M320 278.5v3M384 278.5v6.5"/>
<path d="M60 285v2M110 285v2M160 285v2M172.7 280v2.6M178.4 280v2.6M210 285v2M260 285v2M300 281.5h108M310 285v2M360 285v2"/>
<circle cx="300.9" cy="47.6" r=".51"/>
<circle cx="304.9" cy="47.6" r=".51"/>
</g>
<path d="M142.2 52.7h.2v.3h.2v.1h-.2v.6l.2 .2-.3-.2-.1-.6h-.1zM142.8 53.1l.3-.1 .3 .1 .1 .4-.2 .3-.3 .1-.3-.2v-.3h.1l.3 .4 .2-.3v-.3l-.2-.1-.2 .1-.1 .2h-.1zM231.1 52.7h.2v.3h.2v.1h-.2v.6l.2 .2-.3-.2-.1-.6h-.1zM231.7 53.1l.3-.1 .3 .1 .1 .4-.2 .3-.3 .1-.3-.2v-.3h.1l.3 .4 .2-.3v-.3l-.2-.1-.2 .1-.1 .2h-.1zM131.4 81.1h.1v.7h.4v-.6h.1v.6h.5v-.7h.1v.8h-1.2zM220.3 81.1h.1v.7h.4v-.6h.1v.6h.5v-.7h.1v.8h-1.2zM338.5 279.6l.6-.3v1.4h-.2v-1.2l-.4 .2z" fill="#000"/>
<g fill="none" stroke="#000" stroke-width=".25">
<path d="M98 49.5h2.1v5.1h-2.1zM100.6 49.5h2v5.1h-2zM103.1 49.5h2.1v5.1h-2.1zM105.7 49.5h2v5.1h-2zM108.2 49.5h2v5.1h-2zM110.7 49.5h2.1v5.1h-2.1zM113.3 49.5h2v5.1h-2zM115.8 49.5h2.1v5.1h-2.1zM118.4 49.5h2v5.1h-2zM120.9 49.5h2v5.1h-2zM123.4 49.5h2.1v5.1h-2.1zM126 49.5h2v5.1h-2z"/>
<path d="M128.5 49.5h2.1v5.1h-2.1zM131.1 49.5h2v5.1h-2zM133.6 49.5h2v5.1h-2zM186.9 49.5h2.1v5.1h-2.1zM189.5 49.5h2v5.1h-2zM192 49.5h2.1v5.1h-2.1zM194.6 49.5h2v5.1h-2zM197.1 49.5h2v5.1h-2zM199.6 49.5h2.1v5.1h-2.1zM202.2 49.5h2v5.1h-2zM204.7 49.5h2.1v5.1h-2.1zM207.3 49.5h2v5.1h-2z"/>
<path d="M209.8 49.5h2v5.1h-2zM212.3 49.5h2.1v5.1h-2.1zM214.9 49.5h2v5.1h-2zM217.4 49.5h2.1v5.1h-2.1zM220 49.5h2v5.1h-2zM222.5 49.5h2v5.1h-2zM307.3 59.9h5.1v2.1h-5.1zM322.6 53.3h27.9v73.7h-27.9zM382.5 55.1h2.1v5.1h-2.1zM397 56.6h2.5l-1.2 2.6zM397 59.2h2.5M95.2 64.8h45.8v17.8h-45.8z"/>
<path d="M184.1 64.8h45.8v17.8h-45.8zM307.3 73.7l2.6-1.3v2.5zM307.3 72.4v2.5M382.5 62.7h2.1v5.1h-2.1zM103.1 91.4h2.1v5.1h-2.1zM131.1 91.4h2v5.1h-2zM192 91.4h2.1v5.1h-2.1zM220 91.4h2v5.1h-2zM395 108h2.5v10.1h-2.5zM64.8 135.9h2.5l-1.3 2.5zM64.8 138.4h2.5M74.9 135.9h2.6l-1.3 2.5z"/>
<path d="M74.9 138.4h2.6M85.1 135.9h2.5l-1.2 2.5zM85.1 138.4h2.5M95.2 135.9h2.6l-1.3 2.5zM95.2 138.4h2.6M105.4 135.9h2.5l-1.2 2.5zM105.4 138.4h2.5M115.6 135.9h2.5l-1.3 2.5zM115.6 138.4h2.5M125.7 135.9h2.6l-1.3 2.5zM125.7 138.4h2.6M135.9 135.9h2.5l-1.2 2.5z"/>
<path d="M135.9 138.4h2.5M168.9 123.2h2.5v10.2h-2.5zM64.8 148.6h2.5l-1.3 2.5zM64.8 151.1h2.5M74.9 148.6h2.6l-1.3 2.5zM74.9 151.1h2.6M85.1 148.6h2.5l-1.2 2.5zM85.1 151.1h2.5M95.2 148.6h2.6l-1.3 2.5zM95.2 151.1h2.6M105.4 148.6h2.5l-1.2 2.5zM105.4 151.1h2.5"/>
<path d="M115.6 148.6h2.5l-1.3 2.5zM115.6 151.1h2.5M125.7 148.6h2.6l-1.3 2.5zM125.7 151.1h2.6M135.9 148.6h2.5l-1.2 2.5zM135.9 151.1h2.5M194.3 158.1h22.9v15.3h-22.9zM228.6 151.1l2.5 1.3-2.5 1.3zM230.5 151.8v-.7h.6v2.6h.7v-.7M64.8 176.5h2.5l-1.3 2.6zM64.8 163.8h2.5l-1.3 2.6zM64.8 179.1h2.5"/>
<path d="M64.8 166.4h2.5M74.9 176.5h2.6l-1.3 2.6zM74.9 163.8h2.6l-1.3 2.6zM74.9 179.1h2.6M74.9 166.4h2.6M85.1 176.5h2.5l-1.2 2.6zM85.1 163.8h2.5l-1.2 2.6zM85.1 179.1h2.5M85.1 166.4h2.5M95.2 163.8h2.6l-1.3 2.6zM95.2 176.5h2.6l-1.3 2.6zM95.2 179.1h2.6"/>
<path d="M95.2 166.4h2.6M105.4 163.8h2.5l-1.2 2.6zM105.4 176.5h2.5l-1.2 2.6zM105.4 179.1h2.5M105.4 166.4h2.5M115.6 163.8h2.5l-1.3 2.6zM115.6 176.5h2.5l-1.3 2.6zM115.6 179.1h2.5M115.6 166.4h2.5M125.7 163.8h2.6l-1.3 2.6zM125.7 166.4h2.6M135.9 163.8h2.5l-1.2 2.6z"/>
<path d="M135.9 166.4h2.5M182.5 170.8h2v5.1h-2zM221.9 175.3h2v5h-2zM229.2 168.5h5.1v2.1h-5.1zM238.4 160h2v5.1h-2zM154.3 201.3h2.5v5.1h-2.5zM61.6 237.5h10.2v7.6h-10.2zM77.7 224.8h2.1v5.1h-2.1zM88.9 226.1h2.5M90.2 226.1l1.2 2.5h-2.5zM104.1 224.8h2.6v5.1h-2.6zM112 237.5h2v5.1h-2z"/>
<path d="M63.5 240.7h1.3l-.7 1.2zM63.5 241.9h1.3M93 241.9v3.8M93.5 241.6v1M93.5 243.3v1M93.5 245.1v1"/>
<circle cx="94.4" cy="243.8" r="2.79"/>
</g>
<g fill="none" stroke="#000" stroke-width="1.3">
<circle cx="172.7" cy="212.7" r="1.27"/>
<circle cx="178.4" cy="212.7" r="1.27"/>
<circle cx="172.7" cy="230.5" r="1.27"/>
<circle cx="172.7" cy="238.8" r="1.27"/>
<circle cx="172.7" cy="222.2" r="1.27"/>
<circle cx="178.4" cy="238.8" r="1.27"/>
<circle cx="178.4" cy="222.2" r="1.27"/>
<circle cx="178.4" cy="230.5" r="1.27"/>
<circle cx="172.7" cy="246.4" r="1.27"/>
<circle cx="172.7" cy="254.6" r="1.27"/>
<circle cx="178.4" cy="254.6" r="1.27"/>
<circle cx="178.4" cy="246.4" r="1.27"/>
<circle cx="172.7" cy="278.8" r="1.27"/>
<circle cx="172.7" cy="262.9" r="1.27"/>
<circle cx="172.7" cy="270.5" r="1.27"/>
<circle cx="178.4" cy="278.8" r="1.27"/>
<circle cx="178.4" cy="262.9" r="1.27"/>
<circle cx="178.4" cy="270.5" r="1.27"/>
</g>
<g fill="#c0c0c0" stroke="#c0c0c0" stroke-width=".18">
<path d="M168.9 123.2h2.5v10.2h-2.5z"/>
<path d="M154.3 201.3h2.5v5.1h-2.5z"/>
<path d="M104.1 224.8h2.6v5.1h-2.6z"/>
<path d="M61.6 237.5h10.2v7.6h-10.2z"/>
<path d="M194.3 158.1h22.9v15.3h-22.9z"/>
<path d="M184.1 64.8h45.8v17.8h-45.8z"/>
<path d="M95.2 64.8h45.8v17.8h-45.8z"/>
<path d="M395 108h2.5v10.1h-2.5z"/>
<path d="M322.6 53.3h27.9v73.7h-27.9z"/>
</g>
<g fill="#000" stroke="#000" stroke-width=".18">
<path d="M81.5 85.6h4.6v.5h-4.6zM81.5 84.1h4.6v.5h-4.6zM170.4 85.6h4.6v.5h-4.6zM170.4 84.1h4.6v.5h-4.6zM282.2 133.9h4.6v.5h-4.6zM282.2 132.3h4.6v.5h-4.6zM292.4 133.9h4.5v.5h-4.5zM292.4 132.3h4.5v.5h-4.5zM302.5 133.9h4.6v.5h-4.6zM302.5 132.3h4.6v.5h-4.6zM312.7 133.9h4.5v.5h-4.5zM312.7 132.3h4.5v.5h-4.5z"/>
<path d="M167.9 168.8h4.6v.5h-4.6zM246 168.8h4.6v.5h-4.6zM69.7 243l.5-.6 .5 1.1zM69.2 241.9l1.9 1.9zM93.7 243.8l1-.3v.7z"/>
<circle cx="99.1" cy="45.7" r=".46"/>
<circle cx="101.6" cy="45.7" r=".46"/>
<circle cx="104.1" cy="45.7" r=".46"/>
<circle cx="106.7" cy="45.7" r=".46"/>
<circle cx="109.2" cy="45.7" r=".46"/>
<circle cx="111.8" cy="45.7" r=".46"/>
<circle cx="114.3" cy="45.7" r=".46"/>
<circle cx="116.8" cy="45.7" r=".46"/>
<circle cx="119.4" cy="45.7" r=".46"/>
<circle cx="121.9" cy="45.7" r=".46"/>
<circle cx="124.5" cy="45.7" r=".46"/>
<circle cx="127" cy="45.7" r=".46"/>
<circle cx="129.5" cy="45.7" r=".46"/>
<circle cx="132.1" cy="45.7" r=".46"/>
<circle cx="188" cy="45.7" r=".46"/>
<circle cx="190.5" cy="45.7" r=".46"/>
<circle cx="193" cy="45.7" r=".46"/>
<circle cx="195.6" cy="45.7" r=".46"/>
<circle cx="198.1" cy="45.7" r=".46"/>
<circle cx="200.7" cy="45.7" r=".46"/>
<circle cx="203.2" cy="45.7" r=".46"/>
<circle cx="205.7" cy="45.7" r=".46"/>
<circle cx="208.3" cy="45.7" r=".46"/>
<circle cx="210.8" cy="45.7" r=".46"/>
<circle cx="213.4" cy="45.7" r=".46"/>
<circle cx="215.9" cy="45.7" r=".46"/>
<circle cx="218.4" cy="45.7" r=".46"/>
<circle cx="221" cy="45.7" r=".46"/>
<circle cx="337.8" cy="48.3" r=".46"/>
<circle cx="340.4" cy="48.3" r=".46"/>
<circle cx="83.8" cy="73.7" r=".46"/>
<circle cx="172.7" cy="73.7" r=".46"/>
<circle cx="281.9" cy="66" r=".46"/>
<circle cx="309.9" cy="63.5" r=".46"/>
<circle cx="309.9" cy="71.1" r=".46"/>
<circle cx="383.5" cy="61.5" r=".46"/>
<circle cx="104.1" cy="88.9" r=".46"/>
<circle cx="193" cy="88.9" r=".46"/>
<circle cx="58.4" cy="130.8" r=".46"/>
<circle cx="66" cy="130.8" r=".46"/>
<circle cx="76.2" cy="130.8" r=".46"/>
<circle cx="86.4" cy="130.8" r=".46"/>
<circle cx="96.5" cy="130.8" r=".46"/>
<circle cx="106.7" cy="130.8" r=".46"/>
<circle cx="116.8" cy="130.8" r=".46"/>
<circle cx="127" cy="130.8" r=".46"/>
<circle cx="294.6" cy="127" r=".46"/>
<circle cx="294.6" cy="139.7" r=".46"/>
<circle cx="299.7" cy="127" r=".46"/>
<circle cx="299.7" cy="139.7" r=".46"/>
<circle cx="304.8" cy="127" r=".46"/>
<circle cx="304.8" cy="139.7" r=".46"/>
<circle cx="337.8" cy="132.1" r=".46"/>
<circle cx="58.4" cy="158.8" r=".46"/>
<circle cx="58.4" cy="146.1" r=".46"/>
<circle cx="66" cy="158.8" r=".46"/>
<circle cx="66" cy="146.1" r=".46"/>
<circle cx="76.2" cy="142.2" r=".46"/>
<circle cx="76.2" cy="158.8" r=".46"/>
<circle cx="76.2" cy="156.2" r=".46"/>
<circle cx="76.2" cy="146.1" r=".46"/>
<circle cx="86.4" cy="158.8" r=".46"/>
<circle cx="86.4" cy="146.1" r=".46"/>
<circle cx="86.4" cy="142.2" r=".46"/>
<circle cx="86.4" cy="156.2" r=".46"/>
<circle cx="96.5" cy="156.2" r=".46"/>
<circle cx="96.5" cy="142.2" r=".46"/>
<circle cx="96.5" cy="146.1" r=".46"/>
<circle cx="96.5" cy="158.8" r=".46"/>
<circle cx="106.7" cy="158.8" r=".46"/>
<circle cx="106.7" cy="146.1" r=".46"/>
<circle cx="106.7" cy="156.2" r=".46"/>
<circle cx="106.7" cy="142.2" r=".46"/>
<circle cx="116.8" cy="146.1" r=".46"/>
<circle cx="116.8" cy="142.2" r=".46"/>
<circle cx="116.8" cy="156.2" r=".46"/>
<circle cx="116.8" cy="158.8" r=".46"/>
<circle cx="127" cy="156.2" r=".46"/>
<circle cx="127" cy="146.1" r=".46"/>
<circle cx="127" cy="158.8" r=".46"/>
<circle cx="127" cy="142.2" r=".46"/>
<circle cx="137.2" cy="156.2" r=".46"/>
<circle cx="137.2" cy="142.2" r=".46"/>
<circle cx="149.9" cy="156.2" r=".46"/>
<circle cx="170.2" cy="152.4" r=".46"/>
<circle cx="189.2" cy="152.4" r=".46"/>
<circle cx="222.2" cy="152.4" r=".46"/>
<circle cx="239.4" cy="152.4" r=".46"/>
<circle cx="248.3" cy="152.4" r=".46"/>
<circle cx="66" cy="172.7" r=".46"/>
<circle cx="76.2" cy="170.2" r=".46"/>
<circle cx="76.2" cy="172.7" r=".46"/>
<circle cx="86.4" cy="170.2" r=".46"/>
<circle cx="86.4" cy="172.7" r=".46"/>
<circle cx="96.5" cy="170.2" r=".46"/>
<circle cx="96.5" cy="172.7" r=".46"/>
<circle cx="106.7" cy="170.2" r=".46"/>
<circle cx="106.7" cy="172.7" r=".46"/>
<circle cx="116.8" cy="170.2" r=".46"/>
<circle cx="127" cy="170.2" r=".46"/>
<circle cx="137.2" cy="170.2" r=".46"/>
<circle cx="149.9" cy="170.2" r=".46"/>
<circle cx="222.9" cy="169.5" r=".46"/>
<circle cx="226.1" cy="169.5" r=".46"/>
<circle cx="76.2" cy="184.2" r=".46"/>
<circle cx="86.4" cy="184.2" r=".46"/>
<circle cx="96.5" cy="184.2" r=".46"/>
<circle cx="106.7" cy="184.2" r=".46"/>
<circle cx="116.8" cy="184.2" r=".46"/>
<circle cx="149.9" cy="184.2" r=".46"/>
<circle cx="183.5" cy="185.4" r=".46"/>
<circle cx="203.2" cy="185.4" r=".46"/>
<circle cx="205.1" cy="185.4" r=".46"/>
<circle cx="207" cy="185.4" r=".46"/>
<circle cx="222.9" cy="185.4" r=".46"/>
<circle cx="95.2" cy="233.7" r=".46"/>
<circle cx="95.2" cy="221" r=".46"/>
<circle cx="100.3" cy="233.7" r=".46"/>
<circle cx="78.7" cy="243.8" r=".46"/>
<circle cx="95.2" cy="255.3" r=".46"/>
<circle cx="95.2" cy="245.6" r=".25"/>
<circle cx="95.2" cy="242.1" r=".25"/>
</g>
<g fill="none" stroke="#000" stroke-width=".51">
<path d="M293.2 45.6v4.1M294.8 45.6v4.1M290.1 61.5v4M290.1 69.1v4.1M291.6 61.5v4M291.6 69.1v4.1M308.6 69.2h2.5M308.6 65.4h2.5M181.5 182.4h4M181.5 180.8h4M69.2 239.4v3.8M111 251h4.1"/>
<path d="M111 249.4h4.1"/>
</g>
<path d="M307.3 66.2h5.1v2.3h-5.1z" fill="none" stroke="#000" stroke-width=".3"/>
<use href="#words"/>
</svg>
